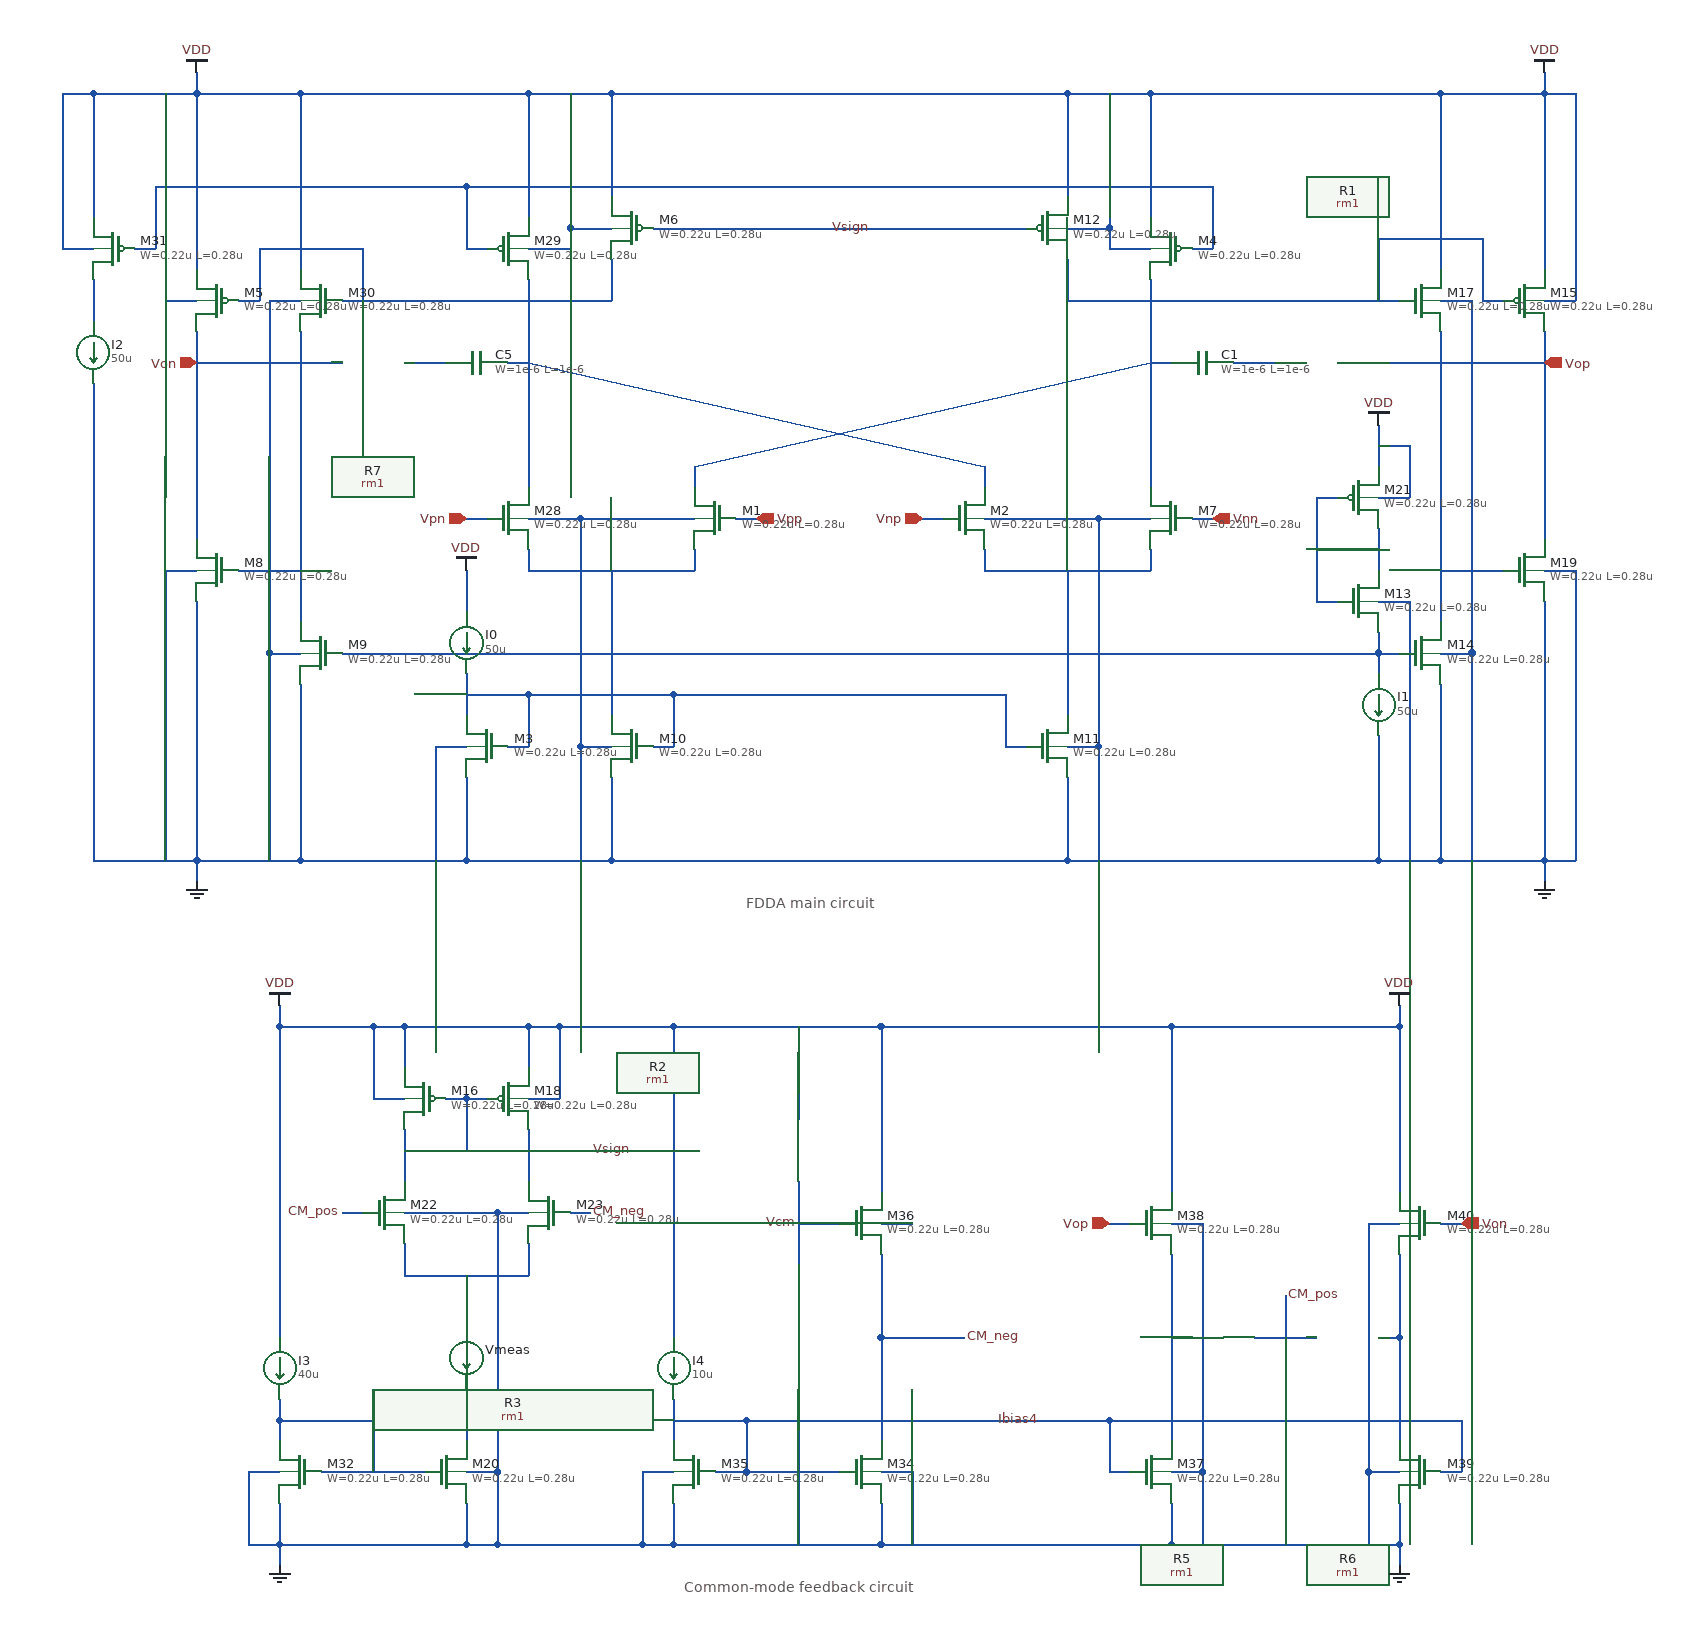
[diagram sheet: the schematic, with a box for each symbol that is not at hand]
v {xschem version=3.4.8RC file_version=1.3}
G {}
K {}
V {}
S {}
F {}
E {}
T {Common-mode feedback circuit} 1130 -250 0 0 0.4 0.4 {}
T {FDDA main circuit} 1190 -910 0 0 0.4 0.4 {}
N 980 -1500 980 -1300 {lab=#net1}
N 1140 -1240 1140 -1220 {lab=#net2}
N 980 -1220 1140 -1220 {lab=#net2}
N 980 -1240 980 -1220 {lab=#net2}
N 1580 -1500 1580 -1300 {lab=#net3}
N 1420 -1240 1420 -1220 {lab=#net4}
N 1420 -1220 1580 -1220 {lab=#net4}
N 1580 -1240 1580 -1220 {lab=#net4}
N 560 -1500 560 -1460 {lab=#net5}
N 560 -1680 560 -1560 {lab=VDD}
N 560 -1680 660 -1680 {lab=VDD}
N 660 -1680 760 -1680 {lab=VDD}
N 560 -1400 560 -940 {lab=GND}
N 660 -1190 660 -940 {lab=GND}
N 560 -940 660 -940 {lab=GND}
N 760 -1110 760 -940 {lab=GND}
N 660 -940 760 -940 {lab=GND}
N 920 -1530 940 -1530 {lab=#net6}
N 700 -1220 760 -1220 {lab=#net7}
N 760 -940 920 -940 {lab=GND}
N 920 -940 1060 -940 {lab=GND}
N 1060 -940 1500 -940 {lab=GND}
N 980 -1680 980 -1560 {lab=VDD}
N 760 -1680 980 -1680 {lab=VDD}
N 1140 -1320 1140 -1300 {lab=#net3}
N 1420 -1320 1420 -1300 {lab=#net1}
N 660 -1450 660 -1250 {lab=Von}
N 760 -1450 760 -1170 {lab=#net7}
N 660 -1680 660 -1510 {lab=VDD}
N 760 -1680 760 -1510 {lab=VDD}
N 800 -1480 980 -1480 {lab=#net1}
N 820 -1530 820 -1480 {lab=#net1}
N 720 -1530 820 -1530 {lab=#net1}
N 720 -1530 720 -1480 {lab=#net1}
N 700 -1480 720 -1480 {lab=#net1}
N 980 -1480 1060 -1480 {lab=#net1}
N 1060 -1520 1060 -1480 {lab=#net1}
N 1060 -1680 1060 -1580 {lab=VDD}
N 980 -1680 1060 -1680 {lab=VDD}
N 1500 -1520 1500 -1480 {lab=#net3}
N 1500 -1480 1580 -1480 {lab=#net3}
N 1060 -1680 1500 -1680 {lab=VDD}
N 1500 -1680 1500 -1580 {lab=VDD}
N 1500 -1680 1580 -1680 {lab=VDD}
N 1580 -1680 1580 -1560 {lab=VDD}
N 1900 -1480 1920 -1480 {lab=#net3}
N 1900 -1540 1900 -1480 {lab=#net3}
N 1800 -1540 1900 -1540 {lab=#net3}
N 1800 -1540 1800 -1480 {lab=#net3}
N 1860 -1680 1860 -1510 {lab=VDD}
N 1960 -1680 1960 -1510 {lab=VDD}
N 1860 -1680 1960 -1680 {lab=VDD}
N 1860 -1450 1860 -1170 {lab=#net8}
N 1860 -1110 1860 -940 {lab=GND}
N 1860 -1220 1920 -1220 {lab=#net8}
N 1960 -1450 1960 -1250 {lab=Vop}
N 1960 -1190 1960 -940 {lab=GND}
N 1860 -940 1960 -940 {lab=GND}
N 1740 -1190 1760 -1190 {lab=#net9}
N 1740 -1290 1740 -1190 {lab=#net9}
N 1740 -1290 1760 -1290 {lab=#net9}
N 1800 -1260 1800 -1220 {lab=#net9}
N 1740 -1240 1800 -1240 {lab=#net9}
N 1800 -1140 1800 -1120 {lab=#net10}
N 1800 -1160 1800 -1140 {lab=#net10}
N 1800 -1060 1800 -940 {lab=GND}
N 1500 -940 1800 -940 {lab=GND}
N 1800 -940 1860 -940 {lab=GND}
N 800 -1140 1800 -1140 {lab=#net10}
N 1800 -1140 1820 -1140 {lab=#net10}
N 1580 -1480 1820 -1480 {lab=#net3}
N 1580 -1680 1860 -1680 {lab=VDD}
N 1620 -1270 1640 -1270 {lab=Vnn}
N 1360 -1270 1380 -1270 {lab=Vnp}
N 1180 -1270 1200 -1270 {lab=Vpp}
N 920 -1270 940 -1270 {lab=Vpn}
N 920 -710 940 -710 {lab=#net11}
N 1140 -1320 1580 -1420 {lab=#net3}
N 980 -1420 1420 -1320 {lab=#net1}
N 980 -570 980 -540 {lab=#net12}
N 860 -540 980 -540 {lab=#net12}
N 860 -570 860 -540 {lab=#net12}
N 920 -1020 920 -940 {lab=GND}
N 1500 -1020 1500 -940 {lab=GND}
N 1060 -1220 1060 -1080 {lab=#net2}
N 1500 -1220 1500 -1080 {lab=#net4}
N 920 -1100 980 -1100 {lab=#net13}
N 980 -1100 980 -1050 {lab=#net13}
N 960 -1050 980 -1050 {lab=#net13}
N 1100 -1050 1120 -1050 {lab=#net13}
N 1120 -1100 1120 -1050 {lab=#net13}
N 980 -1100 1120 -1100 {lab=#net13}
N 1120 -1100 1440 -1100 {lab=#net13}
N 1440 -1100 1440 -1050 {lab=#net13}
N 1440 -1050 1460 -1050 {lab=#net13}
N 600 -1530 620 -1530 {lab=#net6}
N 1060 -1020 1060 -940 {lab=GND}
N 1620 -1530 1640 -1530 {lab=#net6}
N 1020 -1550 1060 -1550 {lab=VDD}
N 1020 -1550 1020 -1530 {lab=VDD}
N 980 -1530 1020 -1530 {lab=VDD}
N 1500 -1550 1540 -1550 {lab=VDD}
N 1540 -1550 1540 -1530 {lab=VDD}
N 1540 -1530 1580 -1530 {lab=VDD}
N 980 -710 1010 -710 {lab=VDD}
N 1960 -1480 1990 -1480 {lab=VDD}
N 920 -350 950 -350 {lab=GND}
N 1860 -1140 1890 -1140 {lab=GND}
N 1800 -1190 1830 -1190 {lab=GND}
N 1960 -1220 1990 -1220 {lab=GND}
N 1860 -1480 1890 -1480 {lab=GND}
N 890 -1050 920 -1050 {lab=GND}
N 1030 -1050 1060 -1050 {lab=GND}
N 730 -1140 760 -1140 {lab=GND}
N 630 -1220 660 -1220 {lab=GND}
N 730 -1480 760 -1480 {lab=GND}
N 1020 -600 1040 -600 {lab=CM_neg}
N 800 -600 820 -600 {lab=CM_pos}
N 780 -350 880 -350 {lab=Ibias3}
N 830 -400 830 -350 {lab=Ibias3}
N 740 -400 830 -400 {lab=Ibias3}
N 1860 -590 1880 -590 {lab=Von}
N 1540 -590 1560 -590 {lab=Vop}
N 980 -660 1040 -660 {lab=Vsign}
N 1600 -320 1600 -280 {lab=GND}
N 1600 -280 1820 -280 {lab=GND}
N 1820 -320 1820 -280 {lab=GND}
N 1790 -350 1820 -350 {lab=GND}
N 1790 -350 1790 -280 {lab=GND}
N 1630 -350 1630 -280 {lab=GND}
N 1600 -350 1630 -350 {lab=GND}
N 1160 -350 1190 -350 {lab=Ibias4}
N 1190 -400 1190 -350 {lab=Ibias4}
N 1120 -400 1190 -400 {lab=Ibias4}
N 1190 -350 1280 -350 {lab=Ibias4}
N 1320 -280 1600 -280 {lab=GND}
N 1320 -320 1320 -280 {lab=GND}
N 1120 -280 1320 -280 {lab=GND}
N 1120 -320 1120 -280 {lab=GND}
N 1090 -350 1120 -350 {lab=GND}
N 1090 -350 1090 -280 {lab=GND}
N 1090 -280 1120 -280 {lab=GND}
N 1320 -350 1350 -350 {lab=GND}
N 1350 -350 1350 -280 {lab=GND}
N 1320 -590 1350 -590 {lab=#net14}
N 1600 -590 1630 -590 {lab=GND}
N 1790 -590 1820 -590 {lab=GND}
N 1320 -480 1400 -480 {lab=CM_neg}
N 1680 -480 1740 -480 {lab=CM_pos}
N 1600 -480 1620 -480 {lab=#net15}
N 1800 -480 1820 -480 {lab=#net16}
N 1640 -1590 1640 -1530 {lab=#net6}
N 920 -1590 1640 -1590 {lab=#net6}
N 920 -1590 920 -1530 {lab=#net6}
N 620 -1590 920 -1590 {lab=#net6}
N 620 -1590 620 -1530 {lab=#net6}
N 1020 -1680 1020 -1550 {lab=VDD}
N 1540 -1680 1540 -1550 {lab=VDD}
N 740 -400 740 -380 {lab=Ibias3}
N 710 -350 740 -350 {lab=GND}
N 920 -280 950 -280 {lab=GND}
N 1890 -1140 1890 -940 {lab=GND}
N 1500 -1050 1530 -1050 {lab=GND}
N 1530 -1050 1530 -940 {lab=GND}
N 1030 -1050 1030 -940 {lab=GND}
N 890 -1050 890 -940 {lab=GND}
N 730 -1140 730 -940 {lab=GND}
N 630 -1220 630 -940 {lab=GND}
N 960 -1420 980 -1420 {lab=#net1}
N 860 -1420 900 -1420 {lab=#net17}
N 660 -1420 800 -1420 {lab=Von}
N 1580 -1420 1600 -1420 {lab=#net3}
N 1660 -1420 1700 -1420 {lab=#net18}
N 1760 -1420 1960 -1420 {lab=Vop}
N 1990 -1680 1990 -1480 {lab=VDD}
N 630 -1480 660 -1480 {lab=VDD}
N 630 -1680 630 -1480 {lab=VDD}
N 530 -1530 560 -1530 {lab=VDD}
N 530 -1680 530 -1530 {lab=VDD}
N 530 -1680 560 -1680 {lab=VDD}
N 950 -600 950 -350 {lab=GND}
N 950 -600 980 -600 {lab=GND}
N 860 -600 950 -600 {lab=GND}
N 1890 -1480 1890 -1140 {lab=GND}
N 1990 -1220 1990 -940 {lab=GND}
N 1530 -1270 1530 -1050 {lab=GND}
N 1530 -1270 1580 -1270 {lab=GND}
N 1420 -1270 1530 -1270 {lab=GND}
N 1030 -1270 1030 -1050 {lab=GND}
N 980 -1270 1030 -1270 {lab=GND}
N 1030 -1270 1140 -1270 {lab=GND}
N 920 -1220 920 -1180 {lab=VDD}
N 920 -1120 920 -1080 {lab=#net13}
N 1800 -1360 1800 -1320 {lab=VDD}
N 1800 -1290 1830 -1290 {lab=VDD}
N 1830 -1340 1830 -1290 {lab=VDD}
N 1800 -1340 1830 -1340 {lab=VDD}
N 1830 -1190 1830 -940 {lab=GND}
N 660 -940 660 -920 {lab=GND}
N 1960 -940 1960 -920 {lab=GND}
N 660 -1700 660 -1680 {lab=VDD}
N 1960 -1700 1960 -1680 {lab=VDD}
N 730 -1480 730 -1140 {lab=GND}
N 1960 -940 1990 -940 {lab=GND}
N 1960 -1680 1990 -1680 {lab=VDD}
N 920 -540 920 -490 {lab=#net12}
N 920 -430 920 -380 {lab=#net19}
N 740 -280 920 -280 {lab=GND}
N 710 -280 740 -280 {lab=GND}
N 740 -420 740 -400 {lab=Ibias3}
N 900 -710 920 -710 {lab=#net11}
N 830 -710 860 -710 {lab=VDD}
N 920 -710 920 -660 {lab=#net11}
N 860 -680 860 -630 {lab=#net11}
N 980 -680 980 -630 {lab=Vsign}
N 920 -320 920 -280 {lab=GND}
N 740 -320 740 -280 {lab=GND}
N 710 -350 710 -280 {lab=GND}
N 950 -350 950 -280 {lab=GND}
N 1860 -350 1880 -350 {lab=Ibias4}
N 1880 -400 1880 -350 {lab=Ibias4}
N 1540 -350 1560 -350 {lab=Ibias4}
N 1540 -400 1540 -350 {lab=Ibias4}
N 1190 -400 1540 -400 {lab=Ibias4}
N 1540 -400 1880 -400 {lab=Ibias4}
N 1120 -420 1120 -380 {lab=Ibias4}
N 950 -280 1090 -280 {lab=GND}
N 740 -780 740 -480 {lab=VDD}
N 830 -780 830 -710 {lab=VDD}
N 860 -780 860 -740 {lab=VDD}
N 740 -780 830 -780 {lab=VDD}
N 830 -780 860 -780 {lab=VDD}
N 860 -780 980 -780 {lab=VDD}
N 980 -780 980 -740 {lab=VDD}
N 980 -780 1010 -780 {lab=VDD}
N 1010 -780 1010 -710 {lab=VDD}
N 1010 -780 1120 -780 {lab=VDD}
N 1120 -780 1120 -480 {lab=VDD}
N 1120 -780 1320 -780 {lab=VDD}
N 1320 -780 1600 -780 {lab=VDD}
N 1600 -780 1820 -780 {lab=VDD}
N 1600 -560 1600 -380 {lab=#net15}
N 1600 -780 1600 -620 {lab=VDD}
N 1320 -560 1320 -480 {lab=CM_neg}
N 1320 -480 1320 -380 {lab=CM_neg}
N 1820 -480 1820 -380 {lab=#net16}
N 1820 -560 1820 -480 {lab=#net16}
N 1820 -780 1820 -620 {lab=VDD}
N 1790 -590 1790 -350 {lab=GND}
N 1630 -590 1630 -350 {lab=GND}
N 1320 -780 1320 -620 {lab=VDD}
N 1710 -520 1710 -480 {lab=CM_pos}
N 740 -800 740 -780 {lab=VDD}
N 1820 -800 1820 -780 {lab=VDD}
N 740 -280 740 -260 {lab=GND}
N 1820 -280 1820 -260 {lab=GND}
N 860 -660 920 -660 {lab=#net11}
N 1100 -1550 1460 -1550 {lab=Vsign}
N 1240 -490 1240 -280 {lab=GND}
N 1240 -630 1240 -550 {lab=Vcm}
N 1240 -590 1280 -590 {lab=Vcm}
N 1240 -780 1240 -690 {lab=VDD}
C {ipin.sym} 920 -1270 0 0 {name=p1 lab=Vpn}
C {ipin.sym} 1200 -1270 0 1 {name=p2 lab=Vpp}
C {ipin.sym} 1360 -1270 0 0 {name=p3 lab=Vnp}
C {ipin.sym} 1640 -1270 0 1 {name=p4 lab=Vnn}
C {isource.sym} 920 -1150 0 0 {name=I0 value=50u}
C {isource.sym} 1800 -1090 0 0 {name=I1 value=50u}
C {isource.sym} 560 -1430 0 0 {name=I2 value=50u}
C {opin.sym} 1960 -1420 0 0 {name=p11 lab=Vop}
C {opin.sym} 660 -1420 0 1 {name=p13 lab=Von}
C {symbols/nfet_03v3.sym} 960 -1270 0 0 {name=M28
L=0.28u
W=0.22u
nf=1
m=1
ad="'int((nf+1)/2) * W/nf * 0.18u'"
pd="'2*int((nf+1)/2) * (W/nf + 0.18u)'"
as="'int((nf+2)/2) * W/nf * 0.18u'"
ps="'2*int((nf+2)/2) * (W/nf + 0.18u)'"
nrd="'0.18u / W'" nrs="'0.18u / W'"
sa=0 sb=0 sd=0
model=nfet_03v3
spiceprefix=X
}
C {symbols/pfet_03v3.sym} 960 -1530 0 0 {name=M29
L=0.28u
W=0.22u
nf=1
m=1
ad="'int((nf+1)/2) * W/nf * 0.18u'"
pd="'2*int((nf+1)/2) * (W/nf + 0.18u)'"
as="'int((nf+2)/2) * W/nf * 0.18u'"
ps="'2*int((nf+2)/2) * (W/nf + 0.18u)'"
nrd="'0.18u / W'" nrs="'0.18u / W'"
sa=0 sb=0 sd=0
model=pfet_03v3
spiceprefix=X
}
C {gnd.sym} 660 -920 0 0 {name=l1 lab=GND}
C {vdd.sym} 660 -1700 0 0 {name=l2 lab=VDD}
C {symbols/nfet_03v3.sym} 780 -1480 0 1 {name=M30
L=0.28u
W=0.22u
nf=1
m=1
ad="'int((nf+1)/2) * W/nf * 0.18u'"
pd="'2*int((nf+1)/2) * (W/nf + 0.18u)'"
as="'int((nf+2)/2) * W/nf * 0.18u'"
ps="'2*int((nf+2)/2) * (W/nf + 0.18u)'"
nrd="'0.18u / W'" nrs="'0.18u / W'"
sa=0 sb=0 sd=0
model=nfet_03v3
spiceprefix=X
}
C {symbols/pfet_03v3.sym} 580 -1530 0 1 {name=M31
L=0.28u
W=0.22u
nf=1
m=1
ad="'int((nf+1)/2) * W/nf * 0.18u'"
pd="'2*int((nf+1)/2) * (W/nf + 0.18u)'"
as="'int((nf+2)/2) * W/nf * 0.18u'"
ps="'2*int((nf+2)/2) * (W/nf + 0.18u)'"
nrd="'0.18u / W'" nrs="'0.18u / W'"
sa=0 sb=0 sd=0
model=pfet_03v3
spiceprefix=X
}
C {symbols/pfet_03v3.sym} 680 -1480 0 1 {name=M5
L=0.28u
W=0.22u
nf=1
m=1
ad="'int((nf+1)/2) * W/nf * 0.18u'"
pd="'2*int((nf+1)/2) * (W/nf + 0.18u)'"
as="'int((nf+2)/2) * W/nf * 0.18u'"
ps="'2*int((nf+2)/2) * (W/nf + 0.18u)'"
nrd="'0.18u / W'" nrs="'0.18u / W'"
sa=0 sb=0 sd=0
model=pfet_03v3
spiceprefix=X
}
C {symbols/pfet_03v3.sym} 1080 -1550 0 1 {name=M6
L=0.28u
W=0.22u
nf=1
m=1
ad="'int((nf+1)/2) * W/nf * 0.18u'"
pd="'2*int((nf+1)/2) * (W/nf + 0.18u)'"
as="'int((nf+2)/2) * W/nf * 0.18u'"
ps="'2*int((nf+2)/2) * (W/nf + 0.18u)'"
nrd="'0.18u / W'" nrs="'0.18u / W'"
sa=0 sb=0 sd=0
model=pfet_03v3
spiceprefix=X
}
C {symbols/pfet_03v3.sym} 1600 -1530 0 1 {name=M4
L=0.28u
W=0.22u
nf=1
m=1
ad="'int((nf+1)/2) * W/nf * 0.18u'"
pd="'2*int((nf+1)/2) * (W/nf + 0.18u)'"
as="'int((nf+2)/2) * W/nf * 0.18u'"
ps="'2*int((nf+2)/2) * (W/nf + 0.18u)'"
nrd="'0.18u / W'" nrs="'0.18u / W'"
sa=0 sb=0 sd=0
model=pfet_03v3
spiceprefix=X
}
C {symbols/pfet_03v3.sym} 1480 -1550 0 0 {name=M12
L=0.28u
W=0.22u
nf=1
m=1
ad="'int((nf+1)/2) * W/nf * 0.18u'"
pd="'2*int((nf+1)/2) * (W/nf + 0.18u)'"
as="'int((nf+2)/2) * W/nf * 0.18u'"
ps="'2*int((nf+2)/2) * (W/nf + 0.18u)'"
nrd="'0.18u / W'" nrs="'0.18u / W'"
sa=0 sb=0 sd=0
model=pfet_03v3
spiceprefix=X
}
C {symbols/pfet_03v3.sym} 1940 -1480 0 0 {name=M15
L=0.28u
W=0.22u
nf=1
m=1
ad="'int((nf+1)/2) * W/nf * 0.18u'"
pd="'2*int((nf+1)/2) * (W/nf + 0.18u)'"
as="'int((nf+2)/2) * W/nf * 0.18u'"
ps="'2*int((nf+2)/2) * (W/nf + 0.18u)'"
nrd="'0.18u / W'" nrs="'0.18u / W'"
sa=0 sb=0 sd=0
model=pfet_03v3
spiceprefix=X
}
C {symbols/pfet_03v3.sym} 880 -710 0 1 {name=M16
L=0.28u
W=0.22u
nf=1
m=1
ad="'int((nf+1)/2) * W/nf * 0.18u'"
pd="'2*int((nf+1)/2) * (W/nf + 0.18u)'"
as="'int((nf+2)/2) * W/nf * 0.18u'"
ps="'2*int((nf+2)/2) * (W/nf + 0.18u)'"
nrd="'0.18u / W'" nrs="'0.18u / W'"
sa=0 sb=0 sd=0
model=pfet_03v3
spiceprefix=X
}
C {symbols/pfet_03v3.sym} 960 -710 0 0 {name=M18
L=0.28u
W=0.22u
nf=1
m=1
ad="'int((nf+1)/2) * W/nf * 0.18u'"
pd="'2*int((nf+1)/2) * (W/nf + 0.18u)'"
as="'int((nf+2)/2) * W/nf * 0.18u'"
ps="'2*int((nf+2)/2) * (W/nf + 0.18u)'"
nrd="'0.18u / W'" nrs="'0.18u / W'"
sa=0 sb=0 sd=0
model=pfet_03v3
spiceprefix=X
}
C {symbols/pfet_03v3.sym} 1780 -1290 0 0 {name=M21
L=0.28u
W=0.22u
nf=1
m=1
ad="'int((nf+1)/2) * W/nf * 0.18u'"
pd="'2*int((nf+1)/2) * (W/nf + 0.18u)'"
as="'int((nf+2)/2) * W/nf * 0.18u'"
ps="'2*int((nf+2)/2) * (W/nf + 0.18u)'"
nrd="'0.18u / W'" nrs="'0.18u / W'"
sa=0 sb=0 sd=0
model=pfet_03v3
spiceprefix=X
}
C {symbols/nfet_03v3.sym} 1160 -1270 0 1 {name=M1
L=0.28u
W=0.22u
nf=1
m=1
ad="'int((nf+1)/2) * W/nf * 0.18u'"
pd="'2*int((nf+1)/2) * (W/nf + 0.18u)'"
as="'int((nf+2)/2) * W/nf * 0.18u'"
ps="'2*int((nf+2)/2) * (W/nf + 0.18u)'"
nrd="'0.18u / W'" nrs="'0.18u / W'"
sa=0 sb=0 sd=0
model=nfet_03v3
spiceprefix=X
}
C {symbols/nfet_03v3.sym} 1400 -1270 0 0 {name=M2
L=0.28u
W=0.22u
nf=1
m=1
ad="'int((nf+1)/2) * W/nf * 0.18u'"
pd="'2*int((nf+1)/2) * (W/nf + 0.18u)'"
as="'int((nf+2)/2) * W/nf * 0.18u'"
ps="'2*int((nf+2)/2) * (W/nf + 0.18u)'"
nrd="'0.18u / W'" nrs="'0.18u / W'"
sa=0 sb=0 sd=0
model=nfet_03v3
spiceprefix=X
}
C {symbols/nfet_03v3.sym} 1600 -1270 0 1 {name=M7
L=0.28u
W=0.22u
nf=1
m=1
ad="'int((nf+1)/2) * W/nf * 0.18u'"
pd="'2*int((nf+1)/2) * (W/nf + 0.18u)'"
as="'int((nf+2)/2) * W/nf * 0.18u'"
ps="'2*int((nf+2)/2) * (W/nf + 0.18u)'"
nrd="'0.18u / W'" nrs="'0.18u / W'"
sa=0 sb=0 sd=0
model=nfet_03v3
spiceprefix=X
}
C {symbols/nfet_03v3.sym} 940 -1050 0 1 {name=M3
L=0.28u
W=0.22u
nf=1
m=1
ad="'int((nf+1)/2) * W/nf * 0.18u'"
pd="'2*int((nf+1)/2) * (W/nf + 0.18u)'"
as="'int((nf+2)/2) * W/nf * 0.18u'"
ps="'2*int((nf+2)/2) * (W/nf + 0.18u)'"
nrd="'0.18u / W'" nrs="'0.18u / W'"
sa=0 sb=0 sd=0
model=nfet_03v3
spiceprefix=X
}
C {symbols/nfet_03v3.sym} 1080 -1050 0 1 {name=M10
L=0.28u
W=0.22u
nf=1
m=1
ad="'int((nf+1)/2) * W/nf * 0.18u'"
pd="'2*int((nf+1)/2) * (W/nf + 0.18u)'"
as="'int((nf+2)/2) * W/nf * 0.18u'"
ps="'2*int((nf+2)/2) * (W/nf + 0.18u)'"
nrd="'0.18u / W'" nrs="'0.18u / W'"
sa=0 sb=0 sd=0
model=nfet_03v3
spiceprefix=X
}
C {symbols/nfet_03v3.sym} 1480 -1050 0 0 {name=M11
L=0.28u
W=0.22u
nf=1
m=1
ad="'int((nf+1)/2) * W/nf * 0.18u'"
pd="'2*int((nf+1)/2) * (W/nf + 0.18u)'"
as="'int((nf+2)/2) * W/nf * 0.18u'"
ps="'2*int((nf+2)/2) * (W/nf + 0.18u)'"
nrd="'0.18u / W'" nrs="'0.18u / W'"
sa=0 sb=0 sd=0
model=nfet_03v3
spiceprefix=X
}
C {symbols/nfet_03v3.sym} 1780 -1190 0 0 {name=M13
L=0.28u
W=0.22u
nf=1
m=1
ad="'int((nf+1)/2) * W/nf * 0.18u'"
pd="'2*int((nf+1)/2) * (W/nf + 0.18u)'"
as="'int((nf+2)/2) * W/nf * 0.18u'"
ps="'2*int((nf+2)/2) * (W/nf + 0.18u)'"
nrd="'0.18u / W'" nrs="'0.18u / W'"
sa=0 sb=0 sd=0
model=nfet_03v3
spiceprefix=X
}
C {symbols/nfet_03v3.sym} 1840 -1140 0 0 {name=M14
L=0.28u
W=0.22u
nf=1
m=1
ad="'int((nf+1)/2) * W/nf * 0.18u'"
pd="'2*int((nf+1)/2) * (W/nf + 0.18u)'"
as="'int((nf+2)/2) * W/nf * 0.18u'"
ps="'2*int((nf+2)/2) * (W/nf + 0.18u)'"
nrd="'0.18u / W'" nrs="'0.18u / W'"
sa=0 sb=0 sd=0
model=nfet_03v3
spiceprefix=X
}
C {symbols/nfet_03v3.sym} 1940 -1220 0 0 {name=M19
L=0.28u
W=0.22u
nf=1
m=1
ad="'int((nf+1)/2) * W/nf * 0.18u'"
pd="'2*int((nf+1)/2) * (W/nf + 0.18u)'"
as="'int((nf+2)/2) * W/nf * 0.18u'"
ps="'2*int((nf+2)/2) * (W/nf + 0.18u)'"
nrd="'0.18u / W'" nrs="'0.18u / W'"
sa=0 sb=0 sd=0
model=nfet_03v3
spiceprefix=X
}
C {symbols/nfet_03v3.sym} 900 -350 0 0 {name=M20
L=0.28u
W=0.22u
nf=1
m=1
ad="'int((nf+1)/2) * W/nf * 0.18u'"
pd="'2*int((nf+1)/2) * (W/nf + 0.18u)'"
as="'int((nf+2)/2) * W/nf * 0.18u'"
ps="'2*int((nf+2)/2) * (W/nf + 0.18u)'"
nrd="'0.18u / W'" nrs="'0.18u / W'"
sa=0 sb=0 sd=0
model=nfet_03v3
spiceprefix=X
}
C {symbols/nfet_03v3.sym} 840 -600 0 0 {name=M22
L=0.28u
W=0.22u
nf=1
m=1
ad="'int((nf+1)/2) * W/nf * 0.18u'"
pd="'2*int((nf+1)/2) * (W/nf + 0.18u)'"
as="'int((nf+2)/2) * W/nf * 0.18u'"
ps="'2*int((nf+2)/2) * (W/nf + 0.18u)'"
nrd="'0.18u / W'" nrs="'0.18u / W'"
sa=0 sb=0 sd=0
model=nfet_03v3
spiceprefix=X
}
C {symbols/nfet_03v3.sym} 1840 -1480 0 0 {name=M17
L=0.28u
W=0.22u
nf=1
m=1
ad="'int((nf+1)/2) * W/nf * 0.18u'"
pd="'2*int((nf+1)/2) * (W/nf + 0.18u)'"
as="'int((nf+2)/2) * W/nf * 0.18u'"
ps="'2*int((nf+2)/2) * (W/nf + 0.18u)'"
nrd="'0.18u / W'" nrs="'0.18u / W'"
sa=0 sb=0 sd=0
model=nfet_03v3
spiceprefix=X
}
C {symbols/nfet_03v3.sym} 680 -1220 0 1 {name=M8
L=0.28u
W=0.22u
nf=1
m=1
ad="'int((nf+1)/2) * W/nf * 0.18u'"
pd="'2*int((nf+1)/2) * (W/nf + 0.18u)'"
as="'int((nf+2)/2) * W/nf * 0.18u'"
ps="'2*int((nf+2)/2) * (W/nf + 0.18u)'"
nrd="'0.18u / W'" nrs="'0.18u / W'"
sa=0 sb=0 sd=0
model=nfet_03v3
spiceprefix=X
}
C {symbols/nfet_03v3.sym} 780 -1140 0 1 {name=M9
L=0.28u
W=0.22u
nf=1
m=1
ad="'int((nf+1)/2) * W/nf * 0.18u'"
pd="'2*int((nf+1)/2) * (W/nf + 0.18u)'"
as="'int((nf+2)/2) * W/nf * 0.18u'"
ps="'2*int((nf+2)/2) * (W/nf + 0.18u)'"
nrd="'0.18u / W'" nrs="'0.18u / W'"
sa=0 sb=0 sd=0
model=nfet_03v3
spiceprefix=X
}
C {symbols/nfet_03v3.sym} 1000 -600 0 1 {name=M23
L=0.28u
W=0.22u
nf=1
m=1
ad="'int((nf+1)/2) * W/nf * 0.18u'"
pd="'2*int((nf+1)/2) * (W/nf + 0.18u)'"
as="'int((nf+2)/2) * W/nf * 0.18u'"
ps="'2*int((nf+2)/2) * (W/nf + 0.18u)'"
nrd="'0.18u / W'" nrs="'0.18u / W'"
sa=0 sb=0 sd=0
model=nfet_03v3
spiceprefix=X
}
C {gnd.sym} 1960 -920 0 0 {name=l11 lab=GND}
C {vdd.sym} 1960 -1700 0 0 {name=l12 lab=VDD}
C {ammeter.sym} 920 -460 0 0 {name=Vmeas savecurrent=true spice_ignore=0}
C {symbols/nfet_03v3.sym} 760 -350 0 1 {name=M32
L=0.28u
W=0.22u
nf=1
m=1
ad="'int((nf+1)/2) * W/nf * 0.18u'"
pd="'2*int((nf+1)/2) * (W/nf + 0.18u)'"
as="'int((nf+2)/2) * W/nf * 0.18u'"
ps="'2*int((nf+2)/2) * (W/nf + 0.18u)'"
nrd="'0.18u / W'" nrs="'0.18u / W'"
sa=0 sb=0 sd=0
model=nfet_03v3
spiceprefix=X
}
C {isource.sym} 740 -450 0 0 {name=I3 value=40u}
C {lab_wire.sym} 1040 -660 0 1 {name=p15 sig_type=std_logic lab=Vsign}
C {lab_wire.sym} 830 -400 0 1 {name=p16 sig_type=std_logic lab=Ibias3}
C {lab_wire.sym} 1040 -600 0 1 {name=p5 sig_type=std_logic lab=CM_neg}
C {lab_wire.sym} 800 -600 0 0 {name=p6 sig_type=std_logic lab=CM_pos}
C {symbols/nfet_03v3.sym} 1300 -350 0 0 {name=M34
L=0.28u
W=0.22u
nf=1
m=1
ad="'int((nf+1)/2) * W/nf * 0.18u'"
pd="'2*int((nf+1)/2) * (W/nf + 0.18u)'"
as="'int((nf+2)/2) * W/nf * 0.18u'"
ps="'2*int((nf+2)/2) * (W/nf + 0.18u)'"
nrd="'0.18u / W'" nrs="'0.18u / W'"
sa=0 sb=0 sd=0
model=nfet_03v3
spiceprefix=X
}
C {symbols/nfet_03v3.sym} 1140 -350 0 1 {name=M35
L=0.28u
W=0.22u
nf=1
m=1
ad="'int((nf+1)/2) * W/nf * 0.18u'"
pd="'2*int((nf+1)/2) * (W/nf + 0.18u)'"
as="'int((nf+2)/2) * W/nf * 0.18u'"
ps="'2*int((nf+2)/2) * (W/nf + 0.18u)'"
nrd="'0.18u / W'" nrs="'0.18u / W'"
sa=0 sb=0 sd=0
model=nfet_03v3
spiceprefix=X
}
C {symbols/nfet_03v3.sym} 1300 -590 0 0 {name=M36
L=0.28u
W=0.22u
nf=1
m=1
ad="'int((nf+1)/2) * W/nf * 0.18u'"
pd="'2*int((nf+1)/2) * (W/nf + 0.18u)'"
as="'int((nf+2)/2) * W/nf * 0.18u'"
ps="'2*int((nf+2)/2) * (W/nf + 0.18u)'"
nrd="'0.18u / W'" nrs="'0.18u / W'"
sa=0 sb=0 sd=0
model=nfet_03v3
spiceprefix=X
}
C {symbols/nfet_03v3.sym} 1580 -350 0 0 {name=M37
L=0.28u
W=0.22u
nf=1
m=1
ad="'int((nf+1)/2) * W/nf * 0.18u'"
pd="'2*int((nf+1)/2) * (W/nf + 0.18u)'"
as="'int((nf+2)/2) * W/nf * 0.18u'"
ps="'2*int((nf+2)/2) * (W/nf + 0.18u)'"
nrd="'0.18u / W'" nrs="'0.18u / W'"
sa=0 sb=0 sd=0
model=nfet_03v3
spiceprefix=X
}
C {symbols/nfet_03v3.sym} 1580 -590 0 0 {name=M38
L=0.28u
W=0.22u
nf=1
m=1
ad="'int((nf+1)/2) * W/nf * 0.18u'"
pd="'2*int((nf+1)/2) * (W/nf + 0.18u)'"
as="'int((nf+2)/2) * W/nf * 0.18u'"
ps="'2*int((nf+2)/2) * (W/nf + 0.18u)'"
nrd="'0.18u / W'" nrs="'0.18u / W'"
sa=0 sb=0 sd=0
model=nfet_03v3
spiceprefix=X
}
C {symbols/nfet_03v3.sym} 1840 -350 0 1 {name=M39
L=0.28u
W=0.22u
nf=1
m=1
ad="'int((nf+1)/2) * W/nf * 0.18u'"
pd="'2*int((nf+1)/2) * (W/nf + 0.18u)'"
as="'int((nf+2)/2) * W/nf * 0.18u'"
ps="'2*int((nf+2)/2) * (W/nf + 0.18u)'"
nrd="'0.18u / W'" nrs="'0.18u / W'"
sa=0 sb=0 sd=0
model=nfet_03v3
spiceprefix=X
}
C {symbols/nfet_03v3.sym} 1840 -590 0 1 {name=M40
L=0.28u
W=0.22u
nf=1
m=1
ad="'int((nf+1)/2) * W/nf * 0.18u'"
pd="'2*int((nf+1)/2) * (W/nf + 0.18u)'"
as="'int((nf+2)/2) * W/nf * 0.18u'"
ps="'2*int((nf+2)/2) * (W/nf + 0.18u)'"
nrd="'0.18u / W'" nrs="'0.18u / W'"
sa=0 sb=0 sd=0
model=nfet_03v3
spiceprefix=X
}
C {opin.sym} 1540 -590 0 1 {name=p17 lab=Vop}
C {opin.sym} 1880 -590 0 0 {name=p18 lab=Von}
C {isource.sym} 1120 -450 0 0 {name=I4 value=10u}
C {lab_wire.sym} 1710 -520 0 1 {name=p9 sig_type=std_logic lab=CM_pos}
C {lab_wire.sym} 1400 -480 0 1 {name=p19 sig_type=std_logic lab=CM_neg}
C {symbols/rm1.sym} 1650 -480 1 0 {name=R5
W=0.6e-6
L=0.6e-6
model=rm1
spiceprefix=X
m=1}
C {symbols/rm1.sym} 1770 -480 1 0 {name=R6
W=0.6e-6
L=0.6e-6
model=rm1
spiceprefix=X
m=1}
C {lab_wire.sym} 1430 -400 0 1 {name=p22 sig_type=std_logic lab=Ibias4}
C {symbols/rm1.sym} 830 -1420 3 0 {name=R7
W=0.6e-6
L=0.6e-6
model=rm1
spiceprefix=X
m=1}
C {symbols/cap_mim_2f0fF.sym} 930 -1420 3 0 {name=C5
W=1e-6
L=1e-6
model=cap_mim_2f0fF
spiceprefix=X
m=1}
C {symbols/rm1.sym} 1730 -1420 1 1 {name=R1
W=0.6e-6
L=0.6e-6
model=rm1
spiceprefix=X
m=1}
C {symbols/cap_mim_2f0fF.sym} 1630 -1420 1 1 {name=C1
W=1e-6
L=1e-6
model=cap_mim_2f0fF
spiceprefix=X
m=1}
C {vdd.sym} 920 -1220 0 0 {name=l3 lab=VDD}
C {vdd.sym} 1800 -1360 0 0 {name=l4 lab=VDD}
C {title-3.sym} 0 0 0 0 {name=F1
title="FDDA with Native MOS CMFB"
author="UFJF On Chip"
rev=1.0
page="1"
pages="1"
lock=true
}
C {lab_wire.sym} 1240 -590 0 0 {name=p8 sig_type=std_logic lab=Vcm}
C {vdd.sym} 740 -800 0 0 {name=l6 lab=VDD}
C {vdd.sym} 1820 -800 0 0 {name=l7 lab=VDD}
C {gnd.sym} 740 -260 0 0 {name=l8 lab=GND}
C {gnd.sym} 1820 -260 0 0 {name=l9 lab=GND}
C {lab_wire.sym} 1270 -1550 0 1 {name=p7 sig_type=std_logic lab=Vsign}
C {symbols/rm1.sym} 1240 -660 2 0 {name=R2
W=0.6e-6
L=0.6e-6
model=rm1
spiceprefix=X
m=1}
C {symbols/rm1.sym} 1240 -520 2 0 {name=R3
W=0.6e-6
L=0.6e-6
model=rm1
spiceprefix=X
m=1}
